VERSION 5.8 ;
BUSBITCHARS "[]" ;
DIVIDERCHAR "/" ;
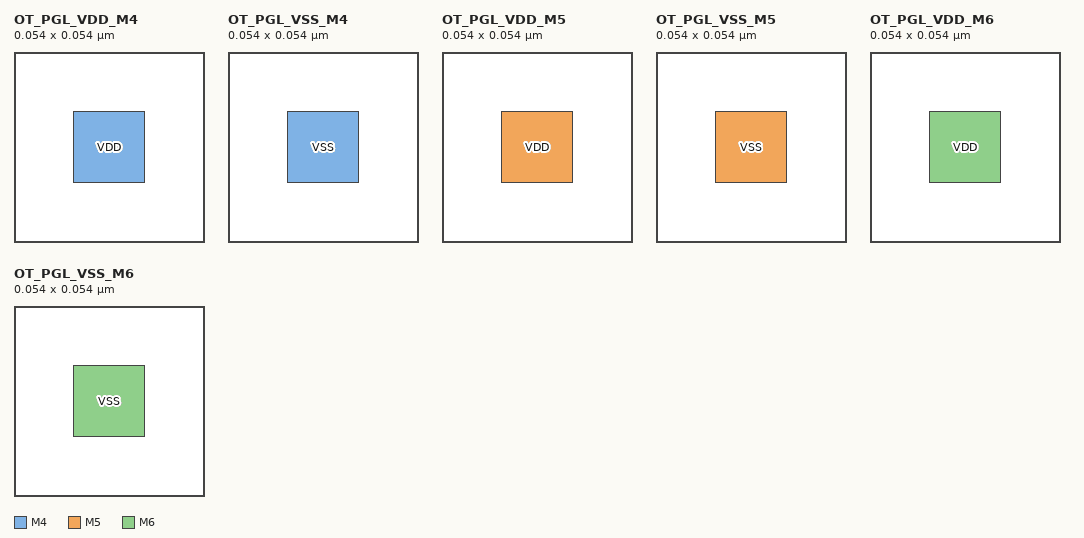
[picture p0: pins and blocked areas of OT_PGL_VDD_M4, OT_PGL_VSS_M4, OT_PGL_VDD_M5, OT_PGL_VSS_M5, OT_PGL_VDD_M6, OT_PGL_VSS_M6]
MACRO OT_PGL_VDD_M4
  CLASS CORE ;
  ORIGIN 0 0 ;
  SIZE 0.054 BY 0.054 ;
  SYMMETRY X Y ;
  PIN VDD
    DIRECTION INOUT ;
    USE POWER ;
    PORT
      LAYER M4 ;
        RECT 0.017 0.017 0.037 0.037 ;
    END
  END VDD
END OT_PGL_VDD_M4
MACRO OT_PGL_VSS_M4
  CLASS CORE ;
  ORIGIN 0 0 ;
  SIZE 0.054 BY 0.054 ;
  SYMMETRY X Y ;
  PIN VSS
    DIRECTION INOUT ;
    USE GROUND ;
    PORT
      LAYER M4 ;
        RECT 0.017 0.017 0.037 0.037 ;
    END
  END VSS
END OT_PGL_VSS_M4
MACRO OT_PGL_VDD_M5
  CLASS CORE ;
  ORIGIN 0 0 ;
  SIZE 0.054 BY 0.054 ;
  SYMMETRY X Y ;
  PIN VDD
    DIRECTION INOUT ;
    USE POWER ;
    PORT
      LAYER M5 ;
        RECT 0.017 0.017 0.037 0.037 ;
    END
  END VDD
END OT_PGL_VDD_M5
MACRO OT_PGL_VSS_M5
  CLASS CORE ;
  ORIGIN 0 0 ;
  SIZE 0.054 BY 0.054 ;
  SYMMETRY X Y ;
  PIN VSS
    DIRECTION INOUT ;
    USE GROUND ;
    PORT
      LAYER M5 ;
        RECT 0.017 0.017 0.037 0.037 ;
    END
  END VSS
END OT_PGL_VSS_M5
MACRO OT_PGL_VDD_M6
  CLASS CORE ;
  ORIGIN 0 0 ;
  SIZE 0.054 BY 0.054 ;
  SYMMETRY X Y ;
  PIN VDD
    DIRECTION INOUT ;
    USE POWER ;
    PORT
      LAYER M6 ;
        RECT 0.017 0.017 0.037 0.037 ;
    END
  END VDD
END OT_PGL_VDD_M6
MACRO OT_PGL_VSS_M6
  CLASS CORE ;
  ORIGIN 0 0 ;
  SIZE 0.054 BY 0.054 ;
  SYMMETRY X Y ;
  PIN VSS
    DIRECTION INOUT ;
    USE GROUND ;
    PORT
      LAYER M6 ;
        RECT 0.017 0.017 0.037 0.037 ;
    END
  END VSS
END OT_PGL_VSS_M6
END LIBRARY
